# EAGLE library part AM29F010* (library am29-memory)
1-Megabit FLASH MEMORY (128 K x 8 bit) 5 V-only

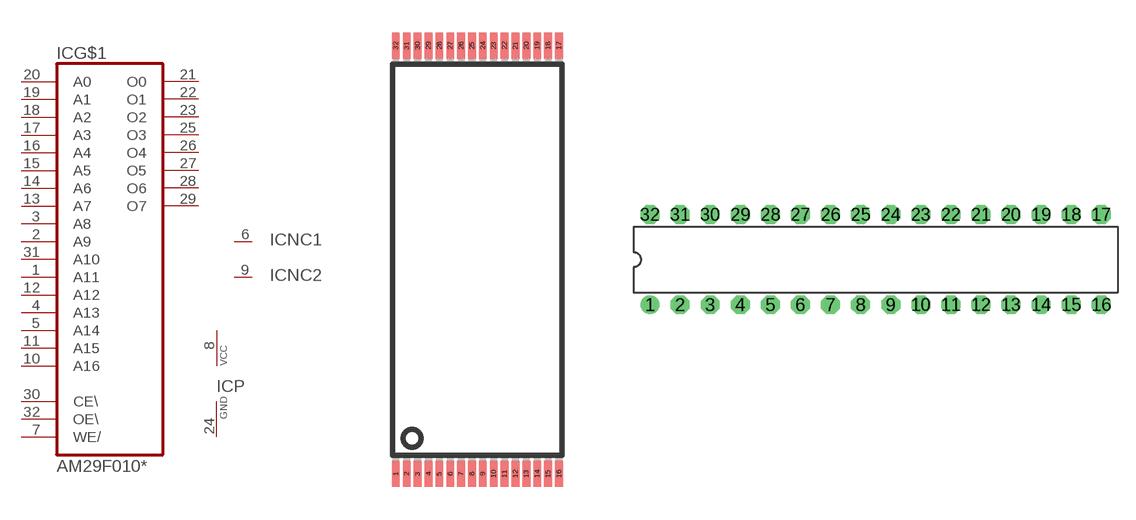
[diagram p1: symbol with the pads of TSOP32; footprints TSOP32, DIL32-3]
Designator prefix IC; gates G$1=AM29F010 P=VCC-GND NC1=NC NC2=NC

## AM29F010E  [TSOP32]
1  G$1:A11  in
2  G$1:A9  in
3  G$1:A8  in
4  G$1:A13  in
5  G$1:A14  in
6  NC1:NC  nc
7  G$1:WE/  in
8  P:VCC  pwr
9  NC2:NC  nc
10  G$1:A16  in
11  G$1:A15  in
12  G$1:A12  in
13  G$1:A7  in
14  G$1:A6  in
15  G$1:A5  in
16  G$1:A4  in
17  G$1:A3  in
18  G$1:A2  in
19  G$1:A1  in
20  G$1:A0  in
21  G$1:O0  hiz
22  G$1:O1  hiz
23  G$1:O2  hiz
24  P:GND  pwr
25  G$1:O3  hiz
26  G$1:O4  hiz
27  G$1:O5  hiz
28  G$1:O6  hiz
29  G$1:O7  hiz
30  G$1:CE\  in
31  G$1:A10  in
32  G$1:OE\  in

## AM29F010P  [DIL32-3]
1  NC1:NC  nc
2  G$1:A16  in
3  G$1:A15  in
4  G$1:A12  in
5  G$1:A7  in
6  G$1:A6  in
7  G$1:A5  in
8  G$1:A4  in
9  G$1:A3  in
10  G$1:A2  in
11  G$1:A1  in
12  G$1:A0  in
13  G$1:O0  hiz
14  G$1:O1  hiz
15  G$1:O2  hiz
16  P:GND  pwr
17  G$1:O3  hiz
18  G$1:O4  hiz
19  G$1:O5  hiz
20  G$1:O6  hiz
21  G$1:O7  hiz
22  G$1:CE\  in
23  G$1:A10  in
24  G$1:OE\  in
25  G$1:A11  in
26  G$1:A9  in
27  G$1:A8  in
28  G$1:A13  in
29  G$1:A14  in
30  NC2:NC  nc
31  G$1:WE/  in
32  P:VCC  pwr

## AM29F010J  [PLCC32R]
Pads as for DIL32-3

## Footprint TSOP32 (pad centres in mm)
Thin Small Outline Plastic Package
smd 0.36 x 1.2: 1 -3.75,-9.85; 2 -3.25,-9.85; 3 -2.75,-9.85; 4 -2.25,-9.85; 5 -1.75,-9.85; 6 -1.25,-9.85; 7 -0.75,-9.85; 8 -0.25,-9.85; 9 0.25,-9.85; 10 0.75,-9.85; 11 1.25,-9.85; 12 1.75,-9.85; 13 2.25,-9.85; 14 2.75,-9.85; 15 3.25,-9.85; 16 3.75,-9.85; 17 3.75,9.85; 18 3.25,9.85; 19 2.75,9.85; 20 2.25,9.85; 21 1.75,9.85; 22 1.25,9.85; 23 0.75,9.85; 24 0.25,9.85; 25 -0.25,9.85; 26 -0.75,9.85; 27 -1.25,9.85; 28 -1.75,9.85; 29 -2.25,9.85; 30 -2.75,9.85; 31 -3.25,9.85; 32 -3.75,9.85

## Footprint DIL32-3 (pad centres in mm)
Dual In Line 0.3 inch
drill 0.813 pad 1.6 round: 1 -19.05,-3.81
drill 0.813 pad 1.6 octagon: 2 -16.51,-3.81; 3 -13.97,-3.81; 4 -11.43,-3.81; 5 -8.89,-3.81; 6 -6.35,-3.81; 7 -3.81,-3.81; 8 -1.27,-3.81; 9 1.27,-3.81; 10 3.81,-3.81; 11 6.35,-3.81; 12 8.89,-3.81; 13 11.43,-3.81; 14 13.97,-3.81; 15 16.51,-3.81; 16 19.05,-3.81; 17 19.05,3.81; 18 16.51,3.81; 19 13.97,3.81; 20 11.43,3.81; 21 8.89,3.81; 22 6.35,3.81; 23 3.81,3.81; 24 1.27,3.81; 25 -1.27,3.81; 26 -3.81,3.81; 27 -6.35,3.81; 28 -8.89,3.81; 29 -11.43,3.81; 30 -13.97,3.81; 31 -16.51,3.81; 32 -19.05,3.81

## Footprint PLCC32R (pad centres in mm)
Plasic Lead Carrier Chip rectangle
smd 0.6 x 2.2: 1 0,6.9; 2 -1.27,6.9; 3 -2.54,6.9; 4 -3.81,6.9; 14 -3.81,-6.9; 15 -2.54,-6.9; 16 -1.27,-6.9; 17 0,-6.9; 18 1.27,-6.9; 19 2.54,-6.9; 20 3.81,-6.9; 30 3.81,6.9; 31 2.54,6.9; 32 1.27,6.9
smd 2.2 x 0.6: 5 -5.7,5.08; 6 -5.7,3.81; 7 -5.7,2.54; 8 -5.7,1.27; 9 -5.7,0; 10 -5.7,-1.27; 11 -5.7,-2.54; 12 -5.7,-3.81; 13 -5.7,-5.08; 21 5.7,-5.08; 22 5.7,-3.81; 23 5.7,-2.54; 24 5.7,-1.27; 25 5.7,0; 26 5.7,1.27; 27 5.7,2.54; 28 5.7,3.81; 29 5.7,5.08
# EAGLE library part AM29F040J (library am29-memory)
4-Megabit FLASH MEMORY (512 K x 8 bit) 5 V-only

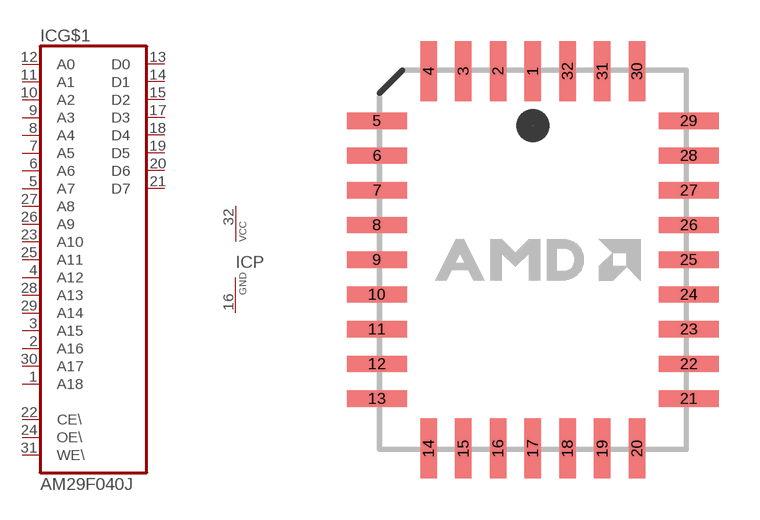
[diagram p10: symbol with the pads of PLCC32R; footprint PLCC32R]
Designator prefix IC; gates G$1=AM29F040 P=VCC-GND

## AM29F040J  [PLCC32R]
1  G$1:A18  in
2  G$1:A16  in
3  G$1:A15  in
4  G$1:A12  in
5  G$1:A7  in
6  G$1:A6  in
7  G$1:A5  in
8  G$1:A4  in
9  G$1:A3  in
10  G$1:A2  in
11  G$1:A1  in
12  G$1:A0  in
13  G$1:D0  hiz
14  G$1:D1  hiz
15  G$1:D2  hiz
16  P:GND  pwr
17  G$1:D3  hiz
18  G$1:D4  hiz
19  G$1:D5  hiz
20  G$1:D6  hiz
21  G$1:D7  hiz
22  G$1:CE\  in
23  G$1:A10  in
24  G$1:OE\  in
25  G$1:A11  in
26  G$1:A9  in
27  G$1:A8  in
28  G$1:A13  in
29  G$1:A14  in
30  G$1:A17  in
31  G$1:WE\  in
32  P:VCC  pwr

## Footprint PLCC32R (pad centres in mm)
Plasic Lead Carrier Chip rectangle
smd 0.6 x 2.2: 1 0,6.9; 2 -1.27,6.9; 3 -2.54,6.9; 4 -3.81,6.9; 14 -3.81,-6.9; 15 -2.54,-6.9; 16 -1.27,-6.9; 17 0,-6.9; 18 1.27,-6.9; 19 2.54,-6.9; 20 3.81,-6.9; 30 3.81,6.9; 31 2.54,6.9; 32 1.27,6.9
smd 2.2 x 0.6: 5 -5.7,5.08; 6 -5.7,3.81; 7 -5.7,2.54; 8 -5.7,1.27; 9 -5.7,0; 10 -5.7,-1.27; 11 -5.7,-2.54; 12 -5.7,-3.81; 13 -5.7,-5.08; 21 5.7,-5.08; 22 5.7,-3.81; 23 5.7,-2.54; 24 5.7,-1.27; 25 5.7,0; 26 5.7,1.27; 27 5.7,2.54; 28 5.7,3.81; 29 5.7,5.08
